VERSION 5.7 ;
  NOWIREEXTENSIONATPIN ON ;
  DIVIDERCHAR "/" ;
  BUSBITCHARS "[]" ;
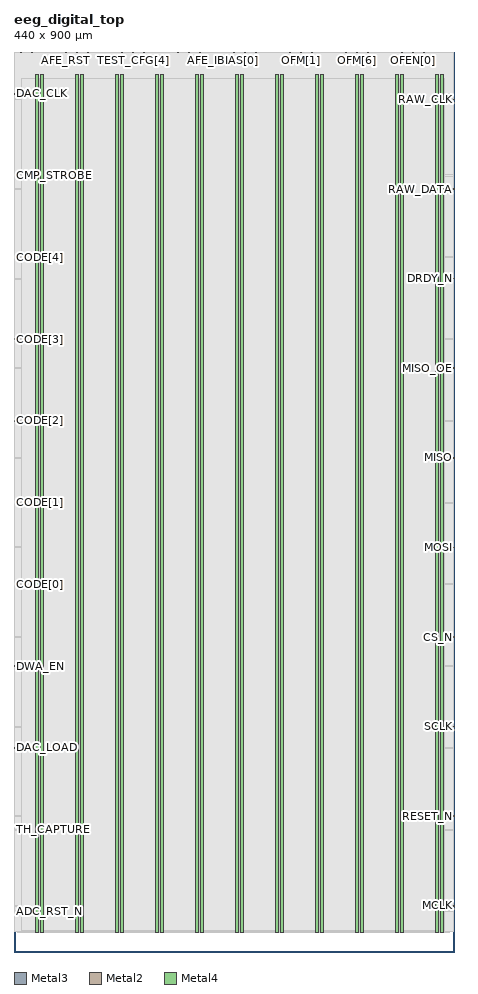
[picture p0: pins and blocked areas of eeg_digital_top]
MACRO eeg_digital_top
  CLASS BLOCK ;
  FOREIGN eeg_digital_top ;
  ORIGIN 0.000 0.000 ;
  SIZE 440.000 BY 900.000 ;
  PIN ADC_RST_N
    DIRECTION OUTPUT ;
    USE SIGNAL ;
    ANTENNADIFFAREA 1.550600 ;
    PORT
      LAYER Metal3 ;
        RECT 0.000 40.320 0.560 40.880 ;
    END
  END ADC_RST_N
  PIN AFE_IBIAS[0]
    DIRECTION OUTPUT ;
    USE SIGNAL ;
    ANTENNADIFFAREA 1.550600 ;
    PORT
      LAYER Metal2 ;
        RECT 208.320 899.440 208.880 900.000 ;
    END
  END AFE_IBIAS[0]
  PIN AFE_IBIAS[1]
    DIRECTION OUTPUT ;
    USE SIGNAL ;
    ANTENNADIFFAREA 1.550600 ;
    PORT
      LAYER Metal2 ;
        RECT 219.520 899.440 220.080 900.000 ;
    END
  END AFE_IBIAS[1]
  PIN AFE_RST
    DIRECTION OUTPUT ;
    USE SIGNAL ;
    ANTENNADIFFAREA 1.550600 ;
    PORT
      LAYER Metal2 ;
        RECT 51.520 899.440 52.080 900.000 ;
    END
  END AFE_RST
  PIN BTRIM_N[0]
    DIRECTION OUTPUT ;
    USE SIGNAL ;
    ANTENNADIFFAREA 1.550600 ;
    PORT
      LAYER Metal2 ;
        RECT 253.120 899.440 253.680 900.000 ;
    END
  END BTRIM_N[0]
  PIN BTRIM_N[1]
    DIRECTION OUTPUT ;
    USE SIGNAL ;
    ANTENNADIFFAREA 1.550600 ;
    PORT
      LAYER Metal2 ;
        RECT 264.320 899.440 264.880 900.000 ;
    END
  END BTRIM_N[1]
  PIN BTRIM_P[0]
    DIRECTION OUTPUT ;
    USE SIGNAL ;
    ANTENNADIFFAREA 1.550600 ;
    PORT
      LAYER Metal2 ;
        RECT 230.720 899.440 231.280 900.000 ;
    END
  END BTRIM_P[0]
  PIN BTRIM_P[1]
    DIRECTION OUTPUT ;
    USE SIGNAL ;
    ANTENNADIFFAREA 1.550600 ;
    PORT
      LAYER Metal2 ;
        RECT 241.920 899.440 242.480 900.000 ;
    END
  END BTRIM_P[1]
  PIN CHOP
    DIRECTION OUTPUT ;
    USE SIGNAL ;
    ANTENNADIFFAREA 1.550600 ;
    PORT
      LAYER Metal2 ;
        RECT 6.720 899.440 7.280 900.000 ;
    END
  END CHOP
  PIN CHOP1
    DIRECTION OUTPUT ;
    USE SIGNAL ;
    ANTENNADIFFAREA 1.550600 ;
    PORT
      LAYER Metal2 ;
        RECT 62.720 899.440 63.280 900.000 ;
    END
  END CHOP1
  PIN CHOP_BLANK
    DIRECTION OUTPUT ;
    USE SIGNAL ;
    ANTENNADIFFAREA 1.550600 ;
    PORT
      LAYER Metal2 ;
        RECT 29.120 899.440 29.680 900.000 ;
    END
  END CHOP_BLANK
  PIN CHOP_EN
    DIRECTION OUTPUT ;
    USE SIGNAL ;
    ANTENNADIFFAREA 1.550600 ;
    PORT
      LAYER Metal2 ;
        RECT 40.320 899.440 40.880 900.000 ;
    END
  END CHOP_EN
  PIN CHOP_OUT
    DIRECTION OUTPUT ;
    USE SIGNAL ;
    ANTENNADIFFAREA 1.550600 ;
    PORT
      LAYER Metal2 ;
        RECT 17.920 899.440 18.480 900.000 ;
    END
  END CHOP_OUT
  PIN CMP_STROBE
    DIRECTION OUTPUT ;
    USE SIGNAL ;
    ANTENNADIFFAREA 1.550600 ;
    PORT
      LAYER Metal3 ;
        RECT 0.000 776.160 0.560 776.720 ;
    END
  END CMP_STROBE
  PIN CODE[0]
    DIRECTION INPUT ;
    USE SIGNAL ;
    ANTENNAGATEAREA 1.353000 ;
    PORT
      LAYER Metal3 ;
        RECT 0.000 367.360 0.560 367.920 ;
    END
  END CODE[0]
  PIN CODE[1]
    DIRECTION INPUT ;
    USE SIGNAL ;
    ANTENNAGATEAREA 1.353000 ;
    PORT
      LAYER Metal3 ;
        RECT 0.000 449.120 0.560 449.680 ;
    END
  END CODE[1]
  PIN CODE[2]
    DIRECTION INPUT ;
    USE SIGNAL ;
    ANTENNAGATEAREA 1.353000 ;
    PORT
      LAYER Metal3 ;
        RECT 0.000 530.880 0.560 531.440 ;
    END
  END CODE[2]
  PIN CODE[3]
    DIRECTION INPUT ;
    USE SIGNAL ;
    ANTENNAGATEAREA 1.353000 ;
    PORT
      LAYER Metal3 ;
        RECT 0.000 612.640 0.560 613.200 ;
    END
  END CODE[3]
  PIN CODE[4]
    DIRECTION INPUT ;
    USE SIGNAL ;
    ANTENNAGATEAREA 1.707000 ;
    PORT
      LAYER Metal3 ;
        RECT 0.000 694.400 0.560 694.960 ;
    END
  END CODE[4]
  PIN CPF_TRIM[0]
    DIRECTION OUTPUT ;
    USE SIGNAL ;
    ANTENNADIFFAREA 1.550600 ;
    PORT
      LAYER Metal2 ;
        RECT 163.520 899.440 164.080 900.000 ;
    END
  END CPF_TRIM[0]
  PIN CPF_TRIM[1]
    DIRECTION OUTPUT ;
    USE SIGNAL ;
    ANTENNADIFFAREA 1.550600 ;
    PORT
      LAYER Metal2 ;
        RECT 174.720 899.440 175.280 900.000 ;
    END
  END CPF_TRIM[1]
  PIN CPF_TRIM[2]
    DIRECTION OUTPUT ;
    USE SIGNAL ;
    ANTENNADIFFAREA 1.550600 ;
    PORT
      LAYER Metal2 ;
        RECT 185.920 899.440 186.480 900.000 ;
    END
  END CPF_TRIM[2]
  PIN CPF_TRIM[3]
    DIRECTION OUTPUT ;
    USE SIGNAL ;
    ANTENNADIFFAREA 1.550600 ;
    PORT
      LAYER Metal2 ;
        RECT 197.120 899.440 197.680 900.000 ;
    END
  END CPF_TRIM[3]
  PIN CS_N
    DIRECTION INPUT ;
    USE SIGNAL ;
    ANTENNAGATEAREA 0.853500 ;
    PORT
      LAYER Metal3 ;
        RECT 439.440 314.720 440.000 315.280 ;
    END
  END CS_N
  PIN DAC_CLK
    DIRECTION OUTPUT ;
    USE SIGNAL ;
    ANTENNADIFFAREA 1.550600 ;
    PORT
      LAYER Metal3 ;
        RECT 0.000 857.920 0.560 858.480 ;
    END
  END DAC_CLK
  PIN DAC_LOAD
    DIRECTION OUTPUT ;
    USE SIGNAL ;
    ANTENNADIFFAREA 1.550600 ;
    PORT
      LAYER Metal3 ;
        RECT 0.000 203.840 0.560 204.400 ;
    END
  END DAC_LOAD
  PIN DRDY_N
    DIRECTION OUTPUT ;
    USE SIGNAL ;
    ANTENNADIFFAREA 1.550600 ;
    PORT
      LAYER Metal3 ;
        RECT 439.440 673.120 440.000 673.680 ;
    END
  END DRDY_N
  PIN DWA_EN
    DIRECTION OUTPUT ;
    USE SIGNAL ;
    ANTENNADIFFAREA 1.550600 ;
    PORT
      LAYER Metal3 ;
        RECT 0.000 285.600 0.560 286.160 ;
    END
  END DWA_EN
  PIN MCLK
    DIRECTION INPUT ;
    USE SIGNAL ;
    ANTENNAGATEAREA 10.823999 ;
    PORT
      LAYER Metal3 ;
        RECT 439.440 45.920 440.000 46.480 ;
    END
  END MCLK
  PIN MISO
    DIRECTION OUTPUT ;
    USE SIGNAL ;
    ANTENNADIFFAREA 1.550600 ;
    PORT
      LAYER Metal3 ;
        RECT 439.440 493.920 440.000 494.480 ;
    END
  END MISO
  PIN MISO_OE
    DIRECTION OUTPUT ;
    USE SIGNAL ;
    ANTENNADIFFAREA 1.550600 ;
    PORT
      LAYER Metal3 ;
        RECT 439.440 583.520 440.000 584.080 ;
    END
  END MISO_OE
  PIN MOSI
    DIRECTION INPUT ;
    USE SIGNAL ;
    ANTENNAGATEAREA 0.853500 ;
    PORT
      LAYER Metal3 ;
        RECT 439.440 404.320 440.000 404.880 ;
    END
  END MOSI
  PIN OFEN[0]
    DIRECTION OUTPUT ;
    USE SIGNAL ;
    ANTENNADIFFAREA 1.550600 ;
    PORT
      LAYER Metal2 ;
        RECT 398.720 899.440 399.280 900.000 ;
    END
  END OFEN[0]
  PIN OFEN[1]
    DIRECTION OUTPUT ;
    USE SIGNAL ;
    ANTENNADIFFAREA 1.550600 ;
    PORT
      LAYER Metal2 ;
        RECT 409.920 899.440 410.480 900.000 ;
    END
  END OFEN[1]
  PIN OFEN[2]
    DIRECTION OUTPUT ;
    USE SIGNAL ;
    ANTENNADIFFAREA 1.550600 ;
    PORT
      LAYER Metal2 ;
        RECT 421.120 899.440 421.680 900.000 ;
    END
  END OFEN[2]
  PIN OFEN[3]
    DIRECTION OUTPUT ;
    USE SIGNAL ;
    ANTENNADIFFAREA 1.550600 ;
    PORT
      LAYER Metal2 ;
        RECT 432.320 899.440 432.880 900.000 ;
    END
  END OFEN[3]
  PIN OFM[0]
    DIRECTION OUTPUT ;
    USE SIGNAL ;
    ANTENNADIFFAREA 1.550600 ;
    PORT
      LAYER Metal2 ;
        RECT 275.520 899.440 276.080 900.000 ;
    END
  END OFM[0]
  PIN OFM[1]
    DIRECTION OUTPUT ;
    USE SIGNAL ;
    ANTENNADIFFAREA 1.550600 ;
    PORT
      LAYER Metal2 ;
        RECT 286.720 899.440 287.280 900.000 ;
    END
  END OFM[1]
  PIN OFM[2]
    DIRECTION OUTPUT ;
    USE SIGNAL ;
    ANTENNADIFFAREA 1.550600 ;
    PORT
      LAYER Metal2 ;
        RECT 297.920 899.440 298.480 900.000 ;
    END
  END OFM[2]
  PIN OFM[3]
    DIRECTION OUTPUT ;
    USE SIGNAL ;
    ANTENNADIFFAREA 1.550600 ;
    PORT
      LAYER Metal2 ;
        RECT 309.120 899.440 309.680 900.000 ;
    END
  END OFM[3]
  PIN OFM[4]
    DIRECTION OUTPUT ;
    USE SIGNAL ;
    ANTENNADIFFAREA 1.550600 ;
    PORT
      LAYER Metal2 ;
        RECT 320.320 899.440 320.880 900.000 ;
    END
  END OFM[4]
  PIN OFM[5]
    DIRECTION OUTPUT ;
    USE SIGNAL ;
    ANTENNADIFFAREA 1.550600 ;
    PORT
      LAYER Metal2 ;
        RECT 331.520 899.440 332.080 900.000 ;
    END
  END OFM[5]
  PIN OFM[6]
    DIRECTION OUTPUT ;
    USE SIGNAL ;
    ANTENNADIFFAREA 1.550600 ;
    PORT
      LAYER Metal2 ;
        RECT 342.720 899.440 343.280 900.000 ;
    END
  END OFM[6]
  PIN OFM[7]
    DIRECTION OUTPUT ;
    USE SIGNAL ;
    ANTENNADIFFAREA 1.550600 ;
    PORT
      LAYER Metal2 ;
        RECT 353.920 899.440 354.480 900.000 ;
    END
  END OFM[7]
  PIN OFM[8]
    DIRECTION OUTPUT ;
    USE SIGNAL ;
    ANTENNADIFFAREA 1.550600 ;
    PORT
      LAYER Metal2 ;
        RECT 365.120 899.440 365.680 900.000 ;
    END
  END OFM[8]
  PIN OFM[9]
    DIRECTION OUTPUT ;
    USE SIGNAL ;
    ANTENNADIFFAREA 1.550600 ;
    PORT
      LAYER Metal2 ;
        RECT 376.320 899.440 376.880 900.000 ;
    END
  END OFM[9]
  PIN OFS
    DIRECTION OUTPUT ;
    USE SIGNAL ;
    ANTENNADIFFAREA 1.550600 ;
    PORT
      LAYER Metal2 ;
        RECT 387.520 899.440 388.080 900.000 ;
    END
  END OFS
  PIN RAW_CLK
    DIRECTION OUTPUT ;
    USE SIGNAL ;
    ANTENNADIFFAREA 1.550600 ;
    PORT
      LAYER Metal3 ;
        RECT 439.440 852.320 440.000 852.880 ;
    END
  END RAW_CLK
  PIN RAW_DATA
    DIRECTION OUTPUT ;
    USE SIGNAL ;
    ANTENNADIFFAREA 1.550600 ;
    PORT
      LAYER Metal3 ;
        RECT 439.440 762.720 440.000 763.280 ;
    END
  END RAW_DATA
  PIN RESET_N
    DIRECTION INPUT ;
    USE SIGNAL ;
    ANTENNAGATEAREA 0.853500 ;
    PORT
      LAYER Metal3 ;
        RECT 439.440 135.520 440.000 136.080 ;
    END
  END RESET_N
  PIN SCLK
    DIRECTION INPUT ;
    USE SIGNAL ;
    ANTENNAGATEAREA 0.853500 ;
    PORT
      LAYER Metal3 ;
        RECT 439.440 225.120 440.000 225.680 ;
    END
  END SCLK
  PIN TEST_CFG[0]
    DIRECTION OUTPUT ;
    USE SIGNAL ;
    ANTENNADIFFAREA 1.550600 ;
    PORT
      LAYER Metal2 ;
        RECT 73.920 899.440 74.480 900.000 ;
    END
  END TEST_CFG[0]
  PIN TEST_CFG[1]
    DIRECTION OUTPUT ;
    USE SIGNAL ;
    ANTENNADIFFAREA 1.550600 ;
    PORT
      LAYER Metal2 ;
        RECT 85.120 899.440 85.680 900.000 ;
    END
  END TEST_CFG[1]
  PIN TEST_CFG[2]
    DIRECTION OUTPUT ;
    USE SIGNAL ;
    ANTENNADIFFAREA 1.550600 ;
    PORT
      LAYER Metal2 ;
        RECT 96.320 899.440 96.880 900.000 ;
    END
  END TEST_CFG[2]
  PIN TEST_CFG[3]
    DIRECTION OUTPUT ;
    USE SIGNAL ;
    ANTENNADIFFAREA 1.550600 ;
    PORT
      LAYER Metal2 ;
        RECT 107.520 899.440 108.080 900.000 ;
    END
  END TEST_CFG[3]
  PIN TEST_CFG[4]
    DIRECTION OUTPUT ;
    USE SIGNAL ;
    ANTENNADIFFAREA 1.550600 ;
    PORT
      LAYER Metal2 ;
        RECT 118.720 899.440 119.280 900.000 ;
    END
  END TEST_CFG[4]
  PIN TEST_CFG[5]
    DIRECTION OUTPUT ;
    USE SIGNAL ;
    ANTENNADIFFAREA 1.550600 ;
    PORT
      LAYER Metal2 ;
        RECT 129.920 899.440 130.480 900.000 ;
    END
  END TEST_CFG[5]
  PIN TEST_CFG[6]
    DIRECTION OUTPUT ;
    USE SIGNAL ;
    ANTENNADIFFAREA 1.550600 ;
    PORT
      LAYER Metal2 ;
        RECT 141.120 899.440 141.680 900.000 ;
    END
  END TEST_CFG[6]
  PIN TEST_CFG[7]
    DIRECTION OUTPUT ;
    USE SIGNAL ;
    ANTENNADIFFAREA 1.550600 ;
    PORT
      LAYER Metal2 ;
        RECT 152.320 899.440 152.880 900.000 ;
    END
  END TEST_CFG[7]
  PIN TH_CAPTURE
    DIRECTION OUTPUT ;
    USE SIGNAL ;
    ANTENNADIFFAREA 1.550600 ;
    PORT
      LAYER Metal3 ;
        RECT 0.000 122.080 0.560 122.640 ;
    END
  END TH_CAPTURE
  PIN VDD
    DIRECTION INOUT ;
    USE POWER ;
    PORT
      LAYER Metal4 ;
        RECT 21.540 19.860 24.540 877.260 ;
    END
    PORT
      LAYER Metal4 ;
        RECT 61.540 19.860 64.540 877.260 ;
    END
    PORT
      LAYER Metal4 ;
        RECT 101.540 19.860 104.540 877.260 ;
    END
    PORT
      LAYER Metal4 ;
        RECT 141.540 19.860 144.540 877.260 ;
    END
    PORT
      LAYER Metal4 ;
        RECT 181.540 19.860 184.540 877.260 ;
    END
    PORT
      LAYER Metal4 ;
        RECT 221.540 19.860 224.540 877.260 ;
    END
    PORT
      LAYER Metal4 ;
        RECT 261.540 19.860 264.540 877.260 ;
    END
    PORT
      LAYER Metal4 ;
        RECT 301.540 19.860 304.540 877.260 ;
    END
    PORT
      LAYER Metal4 ;
        RECT 341.540 19.860 344.540 877.260 ;
    END
    PORT
      LAYER Metal4 ;
        RECT 381.540 19.860 384.540 877.260 ;
    END
    PORT
      LAYER Metal4 ;
        RECT 421.540 19.860 424.540 877.260 ;
    END
  END VDD
  PIN VSS
    DIRECTION INOUT ;
    USE GROUND ;
    PORT
      LAYER Metal4 ;
        RECT 26.240 19.860 29.240 877.260 ;
    END
    PORT
      LAYER Metal4 ;
        RECT 66.240 19.860 69.240 877.260 ;
    END
    PORT
      LAYER Metal4 ;
        RECT 106.240 19.860 109.240 877.260 ;
    END
    PORT
      LAYER Metal4 ;
        RECT 146.240 19.860 149.240 877.260 ;
    END
    PORT
      LAYER Metal4 ;
        RECT 186.240 19.860 189.240 877.260 ;
    END
    PORT
      LAYER Metal4 ;
        RECT 226.240 19.860 229.240 877.260 ;
    END
    PORT
      LAYER Metal4 ;
        RECT 266.240 19.860 269.240 877.260 ;
    END
    PORT
      LAYER Metal4 ;
        RECT 306.240 19.860 309.240 877.260 ;
    END
    PORT
      LAYER Metal4 ;
        RECT 346.240 19.860 349.240 877.260 ;
    END
    PORT
      LAYER Metal4 ;
        RECT 386.240 19.860 389.240 877.260 ;
    END
    PORT
      LAYER Metal4 ;
        RECT 426.240 19.860 429.240 877.260 ;
    END
  END VSS
  OBS
      LAYER Nwell ;
        RECT 3.790 19.730 435.810 877.390 ;
      LAYER Metal1 ;
        RECT 6.720 19.710 432.880 877.410 ;
      LAYER Metal2 ;
        RECT 4.060 899.140 6.420 899.780 ;
        RECT 7.580 899.140 17.620 899.780 ;
        RECT 18.780 899.140 28.820 899.780 ;
        RECT 29.980 899.140 40.020 899.780 ;
        RECT 41.180 899.140 51.220 899.780 ;
        RECT 52.380 899.140 62.420 899.780 ;
        RECT 63.580 899.140 73.620 899.780 ;
        RECT 74.780 899.140 84.820 899.780 ;
        RECT 85.980 899.140 96.020 899.780 ;
        RECT 97.180 899.140 107.220 899.780 ;
        RECT 108.380 899.140 118.420 899.780 ;
        RECT 119.580 899.140 129.620 899.780 ;
        RECT 130.780 899.140 140.820 899.780 ;
        RECT 141.980 899.140 152.020 899.780 ;
        RECT 153.180 899.140 163.220 899.780 ;
        RECT 164.380 899.140 174.420 899.780 ;
        RECT 175.580 899.140 185.620 899.780 ;
        RECT 186.780 899.140 196.820 899.780 ;
        RECT 197.980 899.140 208.020 899.780 ;
        RECT 209.180 899.140 219.220 899.780 ;
        RECT 220.380 899.140 230.420 899.780 ;
        RECT 231.580 899.140 241.620 899.780 ;
        RECT 242.780 899.140 252.820 899.780 ;
        RECT 253.980 899.140 264.020 899.780 ;
        RECT 265.180 899.140 275.220 899.780 ;
        RECT 276.380 899.140 286.420 899.780 ;
        RECT 287.580 899.140 297.620 899.780 ;
        RECT 298.780 899.140 308.820 899.780 ;
        RECT 309.980 899.140 320.020 899.780 ;
        RECT 321.180 899.140 331.220 899.780 ;
        RECT 332.380 899.140 342.420 899.780 ;
        RECT 343.580 899.140 353.620 899.780 ;
        RECT 354.780 899.140 364.820 899.780 ;
        RECT 365.980 899.140 376.020 899.780 ;
        RECT 377.180 899.140 387.220 899.780 ;
        RECT 388.380 899.140 398.420 899.780 ;
        RECT 399.580 899.140 409.620 899.780 ;
        RECT 410.780 899.140 420.820 899.780 ;
        RECT 421.980 899.140 432.020 899.780 ;
        RECT 433.180 899.140 433.860 899.780 ;
        RECT 4.060 19.970 433.860 899.140 ;
      LAYER Metal3 ;
        RECT 0.560 858.780 439.460 899.220 ;
        RECT 0.860 857.620 439.460 858.780 ;
        RECT 0.560 853.180 439.460 857.620 ;
        RECT 0.560 852.020 439.140 853.180 ;
        RECT 0.560 777.020 439.460 852.020 ;
        RECT 0.860 775.860 439.460 777.020 ;
        RECT 0.560 763.580 439.460 775.860 ;
        RECT 0.560 762.420 439.140 763.580 ;
        RECT 0.560 695.260 439.460 762.420 ;
        RECT 0.860 694.100 439.460 695.260 ;
        RECT 0.560 673.980 439.460 694.100 ;
        RECT 0.560 672.820 439.140 673.980 ;
        RECT 0.560 613.500 439.460 672.820 ;
        RECT 0.860 612.340 439.460 613.500 ;
        RECT 0.560 584.380 439.460 612.340 ;
        RECT 0.560 583.220 439.140 584.380 ;
        RECT 0.560 531.740 439.460 583.220 ;
        RECT 0.860 530.580 439.460 531.740 ;
        RECT 0.560 494.780 439.460 530.580 ;
        RECT 0.560 493.620 439.140 494.780 ;
        RECT 0.560 449.980 439.460 493.620 ;
        RECT 0.860 448.820 439.460 449.980 ;
        RECT 0.560 405.180 439.460 448.820 ;
        RECT 0.560 404.020 439.140 405.180 ;
        RECT 0.560 368.220 439.460 404.020 ;
        RECT 0.860 367.060 439.460 368.220 ;
        RECT 0.560 315.580 439.460 367.060 ;
        RECT 0.560 314.420 439.140 315.580 ;
        RECT 0.560 286.460 439.460 314.420 ;
        RECT 0.860 285.300 439.460 286.460 ;
        RECT 0.560 225.980 439.460 285.300 ;
        RECT 0.560 224.820 439.140 225.980 ;
        RECT 0.560 204.700 439.460 224.820 ;
        RECT 0.860 203.540 439.460 204.700 ;
        RECT 0.560 136.380 439.460 203.540 ;
        RECT 0.560 135.220 439.140 136.380 ;
        RECT 0.560 122.940 439.460 135.220 ;
        RECT 0.860 121.780 439.460 122.940 ;
        RECT 0.560 46.780 439.460 121.780 ;
        RECT 0.560 45.620 439.140 46.780 ;
        RECT 0.560 41.180 439.460 45.620 ;
        RECT 0.860 40.020 439.460 41.180 ;
        RECT 0.560 20.020 439.460 40.020 ;
      LAYER Metal4 ;
        RECT 7.420 21.930 21.240 873.510 ;
        RECT 24.840 21.930 25.940 873.510 ;
        RECT 29.540 21.930 61.240 873.510 ;
        RECT 64.840 21.930 65.940 873.510 ;
        RECT 69.540 21.930 101.240 873.510 ;
        RECT 104.840 21.930 105.940 873.510 ;
        RECT 109.540 21.930 141.240 873.510 ;
        RECT 144.840 21.930 145.940 873.510 ;
        RECT 149.540 21.930 181.240 873.510 ;
        RECT 184.840 21.930 185.940 873.510 ;
        RECT 189.540 21.930 221.240 873.510 ;
        RECT 224.840 21.930 225.940 873.510 ;
        RECT 229.540 21.930 261.240 873.510 ;
        RECT 264.840 21.930 265.940 873.510 ;
        RECT 269.540 21.930 301.240 873.510 ;
        RECT 304.840 21.930 305.940 873.510 ;
        RECT 309.540 21.930 341.240 873.510 ;
        RECT 344.840 21.930 345.940 873.510 ;
        RECT 349.540 21.930 381.240 873.510 ;
        RECT 384.840 21.930 385.940 873.510 ;
        RECT 389.540 21.930 421.240 873.510 ;
        RECT 424.840 21.930 425.940 873.510 ;
        RECT 429.540 21.930 430.500 873.510 ;
  END
END eeg_digital_top
END LIBRARY

